VERSION 5.7 ;
BUSBITCHARS "[]" ;
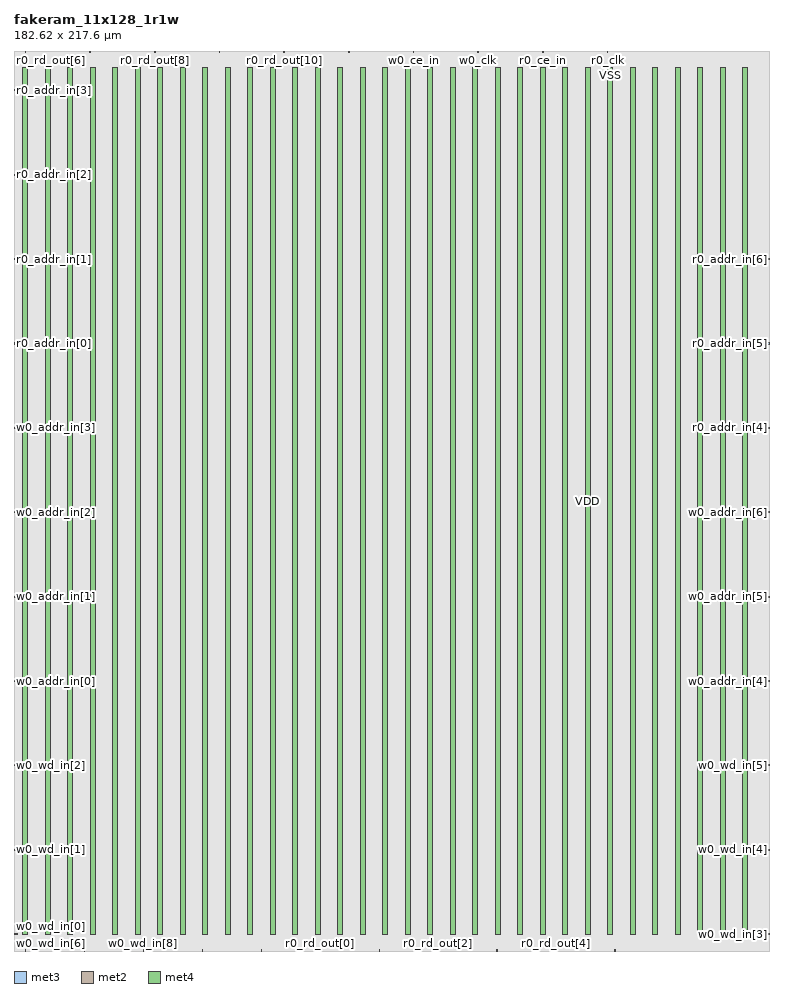
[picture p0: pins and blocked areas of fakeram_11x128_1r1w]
MACRO fakeram_11x128_1r1w
  FOREIGN fakeram_11x128_1r1w 0 0 ;
  SYMMETRY X Y R90 ;
  SIZE 182.620 BY 217.600 ;
  CLASS BLOCK ;
  PIN w0_wd_in[0]
    DIRECTION INPUT ;
    USE SIGNAL ;
    SHAPE ABUTMENT ;
    PORT
      LAYER met3 ;
      RECT 0.000 3.930 0.900 4.230 ;
    END
  END w0_wd_in[0]
  PIN w0_wd_in[1]
    DIRECTION INPUT ;
    USE SIGNAL ;
    SHAPE ABUTMENT ;
    PORT
      LAYER met3 ;
      RECT 0.000 24.330 0.900 24.630 ;
    END
  END w0_wd_in[1]
  PIN w0_wd_in[2]
    DIRECTION INPUT ;
    USE SIGNAL ;
    SHAPE ABUTMENT ;
    PORT
      LAYER met3 ;
      RECT 0.000 44.730 0.900 45.030 ;
    END
  END w0_wd_in[2]
  PIN w0_wd_in[3]
    DIRECTION INPUT ;
    USE SIGNAL ;
    SHAPE ABUTMENT ;
    PORT
      LAYER met3 ;
      RECT 181.720 3.930 182.620 4.230 ;
    END
  END w0_wd_in[3]
  PIN w0_wd_in[4]
    DIRECTION INPUT ;
    USE SIGNAL ;
    SHAPE ABUTMENT ;
    PORT
      LAYER met3 ;
      RECT 181.720 24.330 182.620 24.630 ;
    END
  END w0_wd_in[4]
  PIN w0_wd_in[5]
    DIRECTION INPUT ;
    USE SIGNAL ;
    SHAPE ABUTMENT ;
    PORT
      LAYER met3 ;
      RECT 181.720 44.730 182.620 45.030 ;
    END
  END w0_wd_in[5]
  PIN w0_wd_in[6]
    DIRECTION INPUT ;
    USE SIGNAL ;
    SHAPE ABUTMENT ;
    PORT
      LAYER met2 ;
      RECT 2.690 0.000 2.830 0.420 ;
    END
  END w0_wd_in[6]
  PIN w0_wd_in[7]
    DIRECTION INPUT ;
    USE SIGNAL ;
    SHAPE ABUTMENT ;
    PORT
      LAYER met2 ;
      RECT 16.950 0.000 17.090 0.420 ;
    END
  END w0_wd_in[7]
  PIN w0_wd_in[8]
    DIRECTION INPUT ;
    USE SIGNAL ;
    SHAPE ABUTMENT ;
    PORT
      LAYER met2 ;
      RECT 31.210 0.000 31.350 0.420 ;
    END
  END w0_wd_in[8]
  PIN w0_wd_in[9]
    DIRECTION INPUT ;
    USE SIGNAL ;
    SHAPE ABUTMENT ;
    PORT
      LAYER met2 ;
      RECT 45.470 0.000 45.610 0.420 ;
    END
  END w0_wd_in[9]
  PIN w0_wd_in[10]
    DIRECTION INPUT ;
    USE SIGNAL ;
    SHAPE ABUTMENT ;
    PORT
      LAYER met2 ;
      RECT 59.730 0.000 59.870 0.420 ;
    END
  END w0_wd_in[10]
  PIN r0_rd_out[0]
    DIRECTION OUTPUT ;
    USE SIGNAL ;
    SHAPE ABUTMENT ;
    PORT
      LAYER met2 ;
      RECT 73.990 0.000 74.130 0.420 ;
    END
  END r0_rd_out[0]
  PIN r0_rd_out[1]
    DIRECTION OUTPUT ;
    USE SIGNAL ;
    SHAPE ABUTMENT ;
    PORT
      LAYER met2 ;
      RECT 88.250 0.000 88.390 0.420 ;
    END
  END r0_rd_out[1]
  PIN r0_rd_out[2]
    DIRECTION OUTPUT ;
    USE SIGNAL ;
    SHAPE ABUTMENT ;
    PORT
      LAYER met2 ;
      RECT 102.510 0.000 102.650 0.420 ;
    END
  END r0_rd_out[2]
  PIN r0_rd_out[3]
    DIRECTION OUTPUT ;
    USE SIGNAL ;
    SHAPE ABUTMENT ;
    PORT
      LAYER met2 ;
      RECT 116.770 0.000 116.910 0.420 ;
    END
  END r0_rd_out[3]
  PIN r0_rd_out[4]
    DIRECTION OUTPUT ;
    USE SIGNAL ;
    SHAPE ABUTMENT ;
    PORT
      LAYER met2 ;
      RECT 131.030 0.000 131.170 0.420 ;
    END
  END r0_rd_out[4]
  PIN r0_rd_out[5]
    DIRECTION OUTPUT ;
    USE SIGNAL ;
    SHAPE ABUTMENT ;
    PORT
      LAYER met2 ;
      RECT 145.290 0.000 145.430 0.420 ;
    END
  END r0_rd_out[5]
  PIN r0_rd_out[6]
    DIRECTION OUTPUT ;
    USE SIGNAL ;
    SHAPE ABUTMENT ;
    PORT
      LAYER met2 ;
      RECT 2.690 217.180 2.830 217.600 ;
    END
  END r0_rd_out[6]
  PIN r0_rd_out[7]
    DIRECTION OUTPUT ;
    USE SIGNAL ;
    SHAPE ABUTMENT ;
    PORT
      LAYER met2 ;
      RECT 18.330 217.180 18.470 217.600 ;
    END
  END r0_rd_out[7]
  PIN r0_rd_out[8]
    DIRECTION OUTPUT ;
    USE SIGNAL ;
    SHAPE ABUTMENT ;
    PORT
      LAYER met2 ;
      RECT 33.970 217.180 34.110 217.600 ;
    END
  END r0_rd_out[8]
  PIN r0_rd_out[9]
    DIRECTION OUTPUT ;
    USE SIGNAL ;
    SHAPE ABUTMENT ;
    PORT
      LAYER met2 ;
      RECT 49.610 217.180 49.750 217.600 ;
    END
  END r0_rd_out[9]
  PIN r0_rd_out[10]
    DIRECTION OUTPUT ;
    USE SIGNAL ;
    SHAPE ABUTMENT ;
    PORT
      LAYER met2 ;
      RECT 65.250 217.180 65.390 217.600 ;
    END
  END r0_rd_out[10]
  PIN w0_addr_in[0]
    DIRECTION INPUT ;
    USE SIGNAL ;
    SHAPE ABUTMENT ;
    PORT
      LAYER met3 ;
      RECT 0.000 65.130 0.900 65.430 ;
    END
  END w0_addr_in[0]
  PIN w0_addr_in[1]
    DIRECTION INPUT ;
    USE SIGNAL ;
    SHAPE ABUTMENT ;
    PORT
      LAYER met3 ;
      RECT 0.000 85.530 0.900 85.830 ;
    END
  END w0_addr_in[1]
  PIN w0_addr_in[2]
    DIRECTION INPUT ;
    USE SIGNAL ;
    SHAPE ABUTMENT ;
    PORT
      LAYER met3 ;
      RECT 0.000 105.930 0.900 106.230 ;
    END
  END w0_addr_in[2]
  PIN w0_addr_in[3]
    DIRECTION INPUT ;
    USE SIGNAL ;
    SHAPE ABUTMENT ;
    PORT
      LAYER met3 ;
      RECT 0.000 126.330 0.900 126.630 ;
    END
  END w0_addr_in[3]
  PIN w0_addr_in[4]
    DIRECTION INPUT ;
    USE SIGNAL ;
    SHAPE ABUTMENT ;
    PORT
      LAYER met3 ;
      RECT 181.720 65.130 182.620 65.430 ;
    END
  END w0_addr_in[4]
  PIN w0_addr_in[5]
    DIRECTION INPUT ;
    USE SIGNAL ;
    SHAPE ABUTMENT ;
    PORT
      LAYER met3 ;
      RECT 181.720 85.530 182.620 85.830 ;
    END
  END w0_addr_in[5]
  PIN w0_addr_in[6]
    DIRECTION INPUT ;
    USE SIGNAL ;
    SHAPE ABUTMENT ;
    PORT
      LAYER met3 ;
      RECT 181.720 105.930 182.620 106.230 ;
    END
  END w0_addr_in[6]
  PIN r0_addr_in[0]
    DIRECTION INPUT ;
    USE SIGNAL ;
    SHAPE ABUTMENT ;
    PORT
      LAYER met3 ;
      RECT 0.000 146.730 0.900 147.030 ;
    END
  END r0_addr_in[0]
  PIN r0_addr_in[1]
    DIRECTION INPUT ;
    USE SIGNAL ;
    SHAPE ABUTMENT ;
    PORT
      LAYER met3 ;
      RECT 0.000 167.130 0.900 167.430 ;
    END
  END r0_addr_in[1]
  PIN r0_addr_in[2]
    DIRECTION INPUT ;
    USE SIGNAL ;
    SHAPE ABUTMENT ;
    PORT
      LAYER met3 ;
      RECT 0.000 187.530 0.900 187.830 ;
    END
  END r0_addr_in[2]
  PIN r0_addr_in[3]
    DIRECTION INPUT ;
    USE SIGNAL ;
    SHAPE ABUTMENT ;
    PORT
      LAYER met3 ;
      RECT 0.000 207.930 0.900 208.230 ;
    END
  END r0_addr_in[3]
  PIN r0_addr_in[4]
    DIRECTION INPUT ;
    USE SIGNAL ;
    SHAPE ABUTMENT ;
    PORT
      LAYER met3 ;
      RECT 181.720 126.330 182.620 126.630 ;
    END
  END r0_addr_in[4]
  PIN r0_addr_in[5]
    DIRECTION INPUT ;
    USE SIGNAL ;
    SHAPE ABUTMENT ;
    PORT
      LAYER met3 ;
      RECT 181.720 146.730 182.620 147.030 ;
    END
  END r0_addr_in[5]
  PIN r0_addr_in[6]
    DIRECTION INPUT ;
    USE SIGNAL ;
    SHAPE ABUTMENT ;
    PORT
      LAYER met3 ;
      RECT 181.720 167.130 182.620 167.430 ;
    END
  END r0_addr_in[6]
  PIN w0_we_in
    DIRECTION INPUT ;
    USE SIGNAL ;
    SHAPE ABUTMENT ;
    PORT
      LAYER met2 ;
      RECT 80.890 217.180 81.030 217.600 ;
    END
  END w0_we_in
  PIN w0_ce_in
    DIRECTION INPUT ;
    USE SIGNAL ;
    SHAPE ABUTMENT ;
    PORT
      LAYER met2 ;
      RECT 96.530 217.180 96.670 217.600 ;
    END
  END w0_ce_in
  PIN w0_clk
    DIRECTION INPUT ;
    USE SIGNAL ;
    SHAPE ABUTMENT ;
    PORT
      LAYER met2 ;
      RECT 112.170 217.180 112.310 217.600 ;
    END
  END w0_clk
  PIN r0_ce_in
    DIRECTION INPUT ;
    USE SIGNAL ;
    SHAPE ABUTMENT ;
    PORT
      LAYER met2 ;
      RECT 127.810 217.180 127.950 217.600 ;
    END
  END r0_ce_in
  PIN r0_clk
    DIRECTION INPUT ;
    USE SIGNAL ;
    SHAPE ABUTMENT ;
    PORT
      LAYER met2 ;
      RECT 143.450 217.180 143.590 217.600 ;
    END
  END r0_clk
  PIN VSS
    DIRECTION INOUT ;
    USE GROUND ;
    PORT
      LAYER met4 ;
      RECT 2.160 4.080 3.360 213.520 ;
      RECT 13.040 4.080 14.240 213.520 ;
      RECT 23.920 4.080 25.120 213.520 ;
      RECT 34.800 4.080 36.000 213.520 ;
      RECT 45.680 4.080 46.880 213.520 ;
      RECT 56.560 4.080 57.760 213.520 ;
      RECT 67.440 4.080 68.640 213.520 ;
      RECT 78.320 4.080 79.520 213.520 ;
      RECT 89.200 4.080 90.400 213.520 ;
      RECT 100.080 4.080 101.280 213.520 ;
      RECT 110.960 4.080 112.160 213.520 ;
      RECT 121.840 4.080 123.040 213.520 ;
      RECT 132.720 4.080 133.920 213.520 ;
      RECT 143.600 4.080 144.800 213.520 ;
      RECT 154.480 4.080 155.680 213.520 ;
      RECT 165.360 4.080 166.560 213.520 ;
      RECT 176.240 4.080 177.440 213.520 ;
    END
  END VSS
  PIN VDD
    DIRECTION INOUT ;
    USE POWER ;
    PORT
      LAYER met4 ;
      RECT 7.600 4.080 8.800 213.520 ;
      RECT 18.480 4.080 19.680 213.520 ;
      RECT 29.360 4.080 30.560 213.520 ;
      RECT 40.240 4.080 41.440 213.520 ;
      RECT 51.120 4.080 52.320 213.520 ;
      RECT 62.000 4.080 63.200 213.520 ;
      RECT 72.880 4.080 74.080 213.520 ;
      RECT 83.760 4.080 84.960 213.520 ;
      RECT 94.640 4.080 95.840 213.520 ;
      RECT 105.520 4.080 106.720 213.520 ;
      RECT 116.400 4.080 117.600 213.520 ;
      RECT 127.280 4.080 128.480 213.520 ;
      RECT 138.160 4.080 139.360 213.520 ;
      RECT 149.040 4.080 150.240 213.520 ;
      RECT 159.920 4.080 161.120 213.520 ;
      RECT 170.800 4.080 172.000 213.520 ;
    END
  END VDD
  OBS
    LAYER met1 ;
    RECT 0 0 182.620 217.600 ;
    LAYER met2 ;
    RECT 0 0 182.620 217.600 ;
    LAYER met3 ;
    RECT 0 0 182.620 217.600 ;
    LAYER met4 ;
    RECT 0 0 182.620 217.600 ;
  END
END fakeram_11x128_1r1w

END LIBRARY
